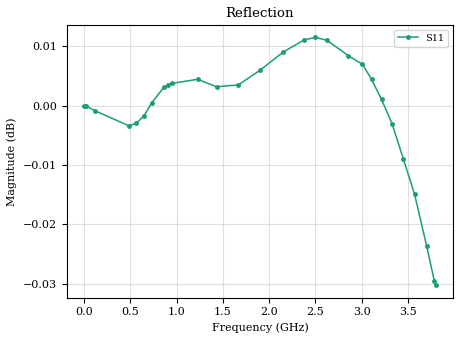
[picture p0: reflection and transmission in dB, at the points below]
! ListType=Lin
!!SAA-2 male open 0.1 to 3800MHz 500 points
# MHz S RI R 50
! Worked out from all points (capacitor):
!   500 points, 100 kHz to 3.8 GHz, reference 50 ohm
!   read as one part to ground: C = 38.2 fF near 15.33 MHz
!   lowest |Z| = 965 ohm at 3.8 GHz (marker M1)
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0.1  1 0.000163
15.33006  1 -0.000312
114.3255  0.9999 -0.00341
479.8469  0.9995 -0.0151
563.6122  0.9995 -0.0178
647.3776  0.9996 -0.0204
731.1429  0.9998 -0.0229
860.5984  1 -0.0267
906.2886  1 -0.0281
951.9788  1 -0.0295
1226.12  0.9998 -0.0378
1431.726  0.9994 -0.044
1667.792  0.9991 -0.0511
1903.858  0.999 -0.0582
2147.538  0.9989 -0.0654
2375.989  0.9987 -0.0718
2497.83  0.9985 -0.0752
2619.67  0.9982 -0.0784
2855.736  0.9974 -0.0845
3008.037  0.9969 -0.0883
3107.032  0.9964 -0.0906
3213.643  0.9958 -0.0929
3327.868  0.9951 -0.0953
3449.709  0.9942 -0.0975
3571.549  0.9933 -0.0996
3701.005  0.9921 -0.1016
3784.77  0.9913 -0.1027
3800  0.9912 -0.1029
